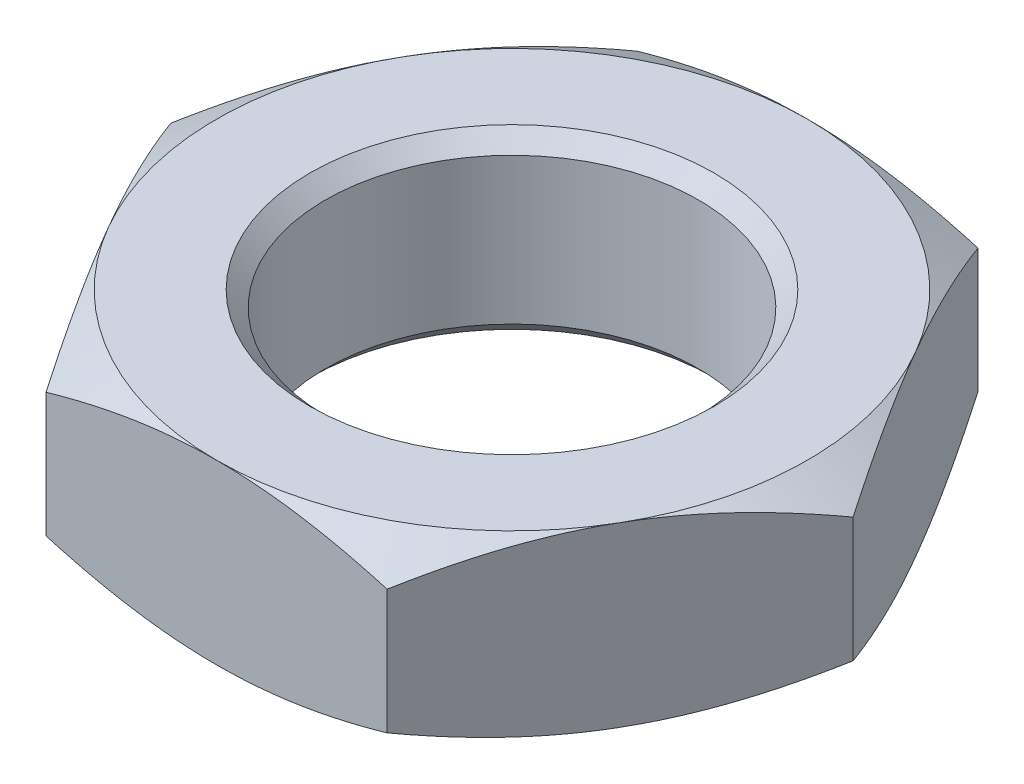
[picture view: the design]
ISO-10303-21;
HEADER;
FILE_DESCRIPTION(('STEP AP214'),'2;1');
FILE_NAME('part.step','',(''),(''),'','','');
FILE_SCHEMA(('AUTOMOTIVE_DESIGN { 1 0 10303 214 1 1 1 1 }'));
ENDSEC;
DATA;
#1=APPLICATION_CONTEXT('core data for automotive mechanical design processes');
#2=APPLICATION_PROTOCOL_DEFINITION('international standard','automotive_design',2000,#1);
#3=PRODUCT_CONTEXT('',#1,'mechanical');
#4=PRODUCT('Part','Part','',(#3));
#5=PRODUCT_RELATED_PRODUCT_CATEGORY('part','',(#4));
#6=PRODUCT_DEFINITION_FORMATION('','',#4);
#7=PRODUCT_DEFINITION_CONTEXT('part definition',#1,'design');
#8=PRODUCT_DEFINITION('design','',#6,#7);
#9=PRODUCT_DEFINITION_SHAPE('','',#8);
#10=(LENGTH_UNIT() NAMED_UNIT(*) SI_UNIT(.MILLI.,.METRE.));
#11=(NAMED_UNIT(*) PLANE_ANGLE_UNIT() SI_UNIT($,.RADIAN.));
#12=(NAMED_UNIT(*) SI_UNIT($,.STERADIAN.) SOLID_ANGLE_UNIT());
#13=UNCERTAINTY_MEASURE_WITH_UNIT(LENGTH_MEASURE(1.E-05),#10,'distance_accuracy_value','');
#14=(GEOMETRIC_REPRESENTATION_CONTEXT(3) GLOBAL_UNCERTAINTY_ASSIGNED_CONTEXT((#13)) GLOBAL_UNIT_ASSIGNED_CONTEXT((#10,
#11,#12)) REPRESENTATION_CONTEXT('',''));
#15=CARTESIAN_POINT('',(0.,0.,0.));
#16=DIRECTION('',(0.,0.,1.));
#17=DIRECTION('',(1.,0.,0.));
#18=AXIS2_PLACEMENT_3D('',#15,#16,#17);
#19=CARTESIAN_POINT('',(0.,2.85,0.));
#20=DIRECTION('',(0.,1.,0.));
#21=DIRECTION('',(0.,0.,1.));
#22=AXIS2_PLACEMENT_3D('',#19,#20,#21);
#23=PLANE('',#22);
#24=CARTESIAN_POINT('',(0.,2.85,0.));
#25=DIRECTION('',(0.,1.,0.));
#26=DIRECTION('',(0.,0.,1.));
#27=AXIS2_PLACEMENT_3D('',#24,#25,#26);
#28=CIRCLE('',#27,6.5);
#29=CARTESIAN_POINT('',(0.,2.85,6.5));
#30=VERTEX_POINT('',#29);
#31=EDGE_CURVE('E11',#30,#30,#28,.F.);
#32=ORIENTED_EDGE('',*,*,#31,.T.);
#33=EDGE_LOOP('',(#32));
#34=FACE_BOUND('',#33,.T.);
#35=CARTESIAN_POINT('',(0.,2.85,0.));
#36=DIRECTION('',(0.,1.,0.));
#37=DIRECTION('',(0.,0.,1.));
#38=AXIS2_PLACEMENT_3D('',#35,#36,#37);
#39=CIRCLE('',#38,9.5);
#40=CARTESIAN_POINT('',(-8.22724133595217,2.85,4.75));
#41=VERTEX_POINT('',#40);
#42=CARTESIAN_POINT('',(0.,2.85,9.5));
#43=VERTEX_POINT('',#42);
#44=EDGE_CURVE('E142',#41,#43,#39,.T.);
#45=ORIENTED_EDGE('',*,*,#44,.T.);
#46=CARTESIAN_POINT('',(8.22724133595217,2.85,4.75));
#47=VERTEX_POINT('',#46);
#48=EDGE_CURVE('E175',#43,#47,#39,.T.);
#49=ORIENTED_EDGE('',*,*,#48,.T.);
#50=CARTESIAN_POINT('',(8.22724133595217,2.85,-4.75));
#51=VERTEX_POINT('',#50);
#52=EDGE_CURVE('E179',#47,#51,#39,.T.);
#53=ORIENTED_EDGE('',*,*,#52,.T.);
#54=CARTESIAN_POINT('',(0.,2.85,-9.5));
#55=VERTEX_POINT('',#54);
#56=EDGE_CURVE('E361',#51,#55,#39,.T.);
#57=ORIENTED_EDGE('',*,*,#56,.T.);
#58=CARTESIAN_POINT('',(-8.22724133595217,2.85,-4.75));
#59=VERTEX_POINT('',#58);
#60=EDGE_CURVE('E55',#55,#59,#39,.T.);
#61=ORIENTED_EDGE('',*,*,#60,.T.);
#62=EDGE_CURVE('E63',#59,#41,#39,.T.);
#63=ORIENTED_EDGE('',*,*,#62,.T.);
#64=EDGE_LOOP('',(#45,#49,#53,#57,#61,#63));
#65=FACE_BOUND('',#64,.T.);
#66=ADVANCED_FACE('F39',(#34,#65),#23,.T.);
#67=CARTESIAN_POINT('',(0.,-2.85,0.));
#68=DIRECTION('',(0.,1.,0.));
#69=DIRECTION('',(0.,0.,1.));
#70=AXIS2_PLACEMENT_3D('',#67,#68,#69);
#71=PLANE('',#70);
#72=CARTESIAN_POINT('',(0.,-2.85,0.));
#73=DIRECTION('',(0.,1.,0.));
#74=DIRECTION('',(0.,0.,1.));
#75=AXIS2_PLACEMENT_3D('',#72,#73,#74);
#76=CIRCLE('',#75,6.50000000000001);
#77=CARTESIAN_POINT('',(0.,-2.85,6.50000000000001));
#78=VERTEX_POINT('',#77);
#79=EDGE_CURVE('E326',#78,#78,#76,.T.);
#80=ORIENTED_EDGE('',*,*,#79,.T.);
#81=EDGE_LOOP('',(#80));
#82=FACE_BOUND('',#81,.T.);
#83=CARTESIAN_POINT('',(0.,-2.85,0.));
#84=DIRECTION('',(0.,1.,0.));
#85=DIRECTION('',(0.,0.,1.));
#86=AXIS2_PLACEMENT_3D('',#83,#84,#85);
#87=CIRCLE('',#86,9.5);
#88=CARTESIAN_POINT('',(0.,-2.85,9.5));
#89=VERTEX_POINT('',#88);
#90=CARTESIAN_POINT('',(8.22724133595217,-2.85,4.75));
#91=VERTEX_POINT('',#90);
#92=EDGE_CURVE('E130',#89,#91,#87,.T.);
#93=ORIENTED_EDGE('',*,*,#92,.F.);
#94=CARTESIAN_POINT('',(-8.22724133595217,-2.85,4.75));
#95=VERTEX_POINT('',#94);
#96=EDGE_CURVE('E145',#95,#89,#87,.T.);
#97=ORIENTED_EDGE('',*,*,#96,.F.);
#98=CARTESIAN_POINT('',(-8.22724133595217,-2.85,-4.75));
#99=VERTEX_POINT('',#98);
#100=EDGE_CURVE('E367',#99,#95,#87,.T.);
#101=ORIENTED_EDGE('',*,*,#100,.F.);
#102=CARTESIAN_POINT('',(0.,-2.85,-9.5));
#103=VERTEX_POINT('',#102);
#104=EDGE_CURVE('E173',#103,#99,#87,.T.);
#105=ORIENTED_EDGE('',*,*,#104,.F.);
#106=CARTESIAN_POINT('',(8.22724133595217,-2.85,-4.75));
#107=VERTEX_POINT('',#106);
#108=EDGE_CURVE('E169',#107,#103,#87,.T.);
#109=ORIENTED_EDGE('',*,*,#108,.F.);
#110=EDGE_CURVE('E143',#91,#107,#87,.T.);
#111=ORIENTED_EDGE('',*,*,#110,.F.);
#112=EDGE_LOOP('',(#93,#97,#101,#105,#109,#111));
#113=FACE_BOUND('',#112,.T.);
#114=ADVANCED_FACE('F167',(#82,#113),#71,.F.);
#115=CARTESIAN_POINT('',(0.,2.85,0.));
#116=DIRECTION('',(0.,-1.,0.));
#117=DIRECTION('',(0.,0.,-1.));
#118=AXIS2_PLACEMENT_3D('',#115,#116,#117);
#119=CYLINDRICAL_SURFACE('',#118,6.);
#120=CARTESIAN_POINT('',(0.,-2.34999999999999,0.));
#121=DIRECTION('',(0.,1.,0.));
#122=DIRECTION('',(0.,0.,1.));
#123=AXIS2_PLACEMENT_3D('',#120,#121,#122);
#124=CIRCLE('',#123,6.);
#125=CARTESIAN_POINT('',(0.,-2.34999999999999,6.));
#126=VERTEX_POINT('',#125);
#127=EDGE_CURVE('E48',#126,#126,#124,.F.);
#128=ORIENTED_EDGE('',*,*,#127,.T.);
#129=EDGE_LOOP('',(#128));
#130=FACE_BOUND('',#129,.T.);
#131=CARTESIAN_POINT('',(0.,2.35,0.));
#132=DIRECTION('',(0.,1.,0.));
#133=DIRECTION('',(0.,0.,1.));
#134=AXIS2_PLACEMENT_3D('',#131,#132,#133);
#135=CIRCLE('',#134,6.);
#136=CARTESIAN_POINT('',(0.,2.35,6.));
#137=VERTEX_POINT('',#136);
#138=EDGE_CURVE('E330',#137,#137,#135,.T.);
#139=ORIENTED_EDGE('',*,*,#138,.T.);
#140=EDGE_LOOP('',(#139));
#141=FACE_BOUND('',#140,.T.);
#142=ADVANCED_FACE('F202',(#130,#141),#119,.F.);
#143=CARTESIAN_POINT('',(0.,-2.85,0.));
#144=DIRECTION('',(0.,1.,0.));
#145=DIRECTION('',(0.,0.,1.));
#146=AXIS2_PLACEMENT_3D('',#143,#144,#145);
#147=CONICAL_SURFACE('',#146,9.5,1.0471975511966);
#148=CARTESIAN_POINT('',(5.4847120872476,-2.00142755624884,9.5002));
#149=CARTESIAN_POINT('',(5.60528058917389,-2.07102656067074,9.2913692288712));
#150=CARTESIAN_POINT('',(5.72629863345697,-2.13746669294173,9.08175982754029));
#151=CARTESIAN_POINT('',(5.96930519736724,-2.26315271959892,8.66086011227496));
#152=CARTESIAN_POINT('',(6.09129402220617,-2.32239624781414,8.44956926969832));
#153=CARTESIAN_POINT('',(6.45922610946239,-2.48818542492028,7.81229220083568));
#154=CARTESIAN_POINT('',(6.70662183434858,-2.58248555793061,7.38379023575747));
#155=CARTESIAN_POINT('',(7.07683821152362,-2.69306129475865,6.74255666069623));
#156=CARTESIAN_POINT('',(7.19855281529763,-2.72456017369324,6.53174078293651));
#157=CARTESIAN_POINT('',(7.44254555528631,-2.77738179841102,6.10913296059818));
#158=CARTESIAN_POINT('',(7.56482370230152,-2.79870434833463,5.89734099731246));
#159=CARTESIAN_POINT('',(7.80958396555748,-2.83062697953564,5.47340378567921));
#160=CARTESIAN_POINT('',(7.93206566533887,-2.84123980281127,5.26125925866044));
#161=CARTESIAN_POINT('',(8.17714220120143,-2.85151746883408,4.83677424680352));
#162=CARTESIAN_POINT('',(8.29973703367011,-2.85118264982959,4.62443376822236));
#163=CARTESIAN_POINT('',(8.5289310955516,-2.84032663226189,4.22745800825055));
#164=CARTESIAN_POINT('',(8.63554650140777,-2.83112973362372,4.04279470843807));
#165=CARTESIAN_POINT('',(8.84852796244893,-2.80463460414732,3.67389999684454));
#166=CARTESIAN_POINT('',(8.95489399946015,-2.78733580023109,3.48966861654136));
#167=CARTESIAN_POINT('',(9.27357996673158,-2.72369551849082,2.937688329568));
#168=CARTESIAN_POINT('',(9.48533580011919,-2.66561809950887,2.57091646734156));
#169=CARTESIAN_POINT('',(9.91109368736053,-2.52042398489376,1.83348217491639));
#170=CARTESIAN_POINT('',(10.1250414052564,-2.43269183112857,1.46291385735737));
#171=CARTESIAN_POINT('',(10.5497463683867,-2.23357626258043,0.72730328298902));
#172=CARTESIAN_POINT('',(10.7605090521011,-2.12223961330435,0.362251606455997));
#173=CARTESIAN_POINT('',(10.9697705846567,-2.00142755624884,-0.000200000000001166));
#174=B_SPLINE_CURVE_WITH_KNOTS('',3,(#148,#149,#150,#151,#152,#153,#154,#155,#156,#157,#158,
#159,#160,#161,#162,#163,#164,#165,#166,#167,#168,#169,#170,#171,#172,#173),.UNSPECIFIED.,.F.,
.F.,(4,2,2,2,2,2,2,2,2,2,2,2,4),(0.,0.752880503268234,1.50600787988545,3.0154687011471,
3.75167336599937,4.48789219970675,5.22323407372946,5.95855322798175,6.59868084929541,
7.23885375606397,8.52010929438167,9.82978009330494,11.1368800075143),.UNSPECIFIED.);
#175=CARTESIAN_POINT('',(10.9696551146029,-2.00149422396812,0.));
#176=VERTEX_POINT('',#175);
#177=EDGE_CURVE('E148',#91,#176,#174,.T.);
#178=ORIENTED_EDGE('',*,*,#177,.F.);
#179=ORIENTED_EDGE('',*,*,#110,.T.);
#180=CARTESIAN_POINT('',(10.9697705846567,-2.00142755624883,0.000199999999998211));
#181=CARTESIAN_POINT('',(10.8492020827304,-2.07102656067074,-0.208630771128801));
#182=CARTESIAN_POINT('',(10.7281840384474,-2.13746669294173,-0.41824017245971));
#183=CARTESIAN_POINT('',(10.4851774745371,-2.26315271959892,-0.839139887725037));
#184=CARTESIAN_POINT('',(10.3631886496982,-2.32239624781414,-1.05043073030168));
#185=CARTESIAN_POINT('',(9.99525656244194,-2.48818542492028,-1.68770779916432));
#186=CARTESIAN_POINT('',(9.74786083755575,-2.58248555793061,-2.11620976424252));
#187=CARTESIAN_POINT('',(9.37764446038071,-2.69306129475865,-2.75744333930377));
#188=CARTESIAN_POINT('',(9.2559298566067,-2.72456017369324,-2.96825921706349));
#189=CARTESIAN_POINT('',(9.01193711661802,-2.77738179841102,-3.39086703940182));
#190=CARTESIAN_POINT('',(8.88965896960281,-2.79870434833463,-3.60265900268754));
#191=CARTESIAN_POINT('',(8.64489870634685,-2.83062697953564,-4.02659621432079));
#192=CARTESIAN_POINT('',(8.52241700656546,-2.84123980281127,-4.23874074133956));
#193=CARTESIAN_POINT('',(8.2773404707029,-2.85151746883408,-4.66322575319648));
#194=CARTESIAN_POINT('',(8.15474563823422,-2.85118264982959,-4.87556623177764));
#195=CARTESIAN_POINT('',(7.92555157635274,-2.84032663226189,-5.27254199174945));
#196=CARTESIAN_POINT('',(7.81893617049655,-2.83112973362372,-5.45720529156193));
#197=CARTESIAN_POINT('',(7.6059547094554,-2.80463460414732,-5.82610000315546));
#198=CARTESIAN_POINT('',(7.49958867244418,-2.78733580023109,-6.01033138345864));
#199=CARTESIAN_POINT('',(7.18090270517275,-2.72369551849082,-6.562311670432));
#200=CARTESIAN_POINT('',(6.96914687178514,-2.66561809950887,-6.92908353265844));
#201=CARTESIAN_POINT('',(6.5433889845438,-2.52042398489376,-7.66651782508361));
#202=CARTESIAN_POINT('',(6.32944126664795,-2.43269183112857,-8.03708614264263));
#203=CARTESIAN_POINT('',(5.90473630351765,-2.23357626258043,-8.77269671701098));
#204=CARTESIAN_POINT('',(5.69397361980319,-2.12223961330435,-9.137748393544));
#205=CARTESIAN_POINT('',(5.4847120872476,-2.00142755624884,-9.5002));
#206=B_SPLINE_CURVE_WITH_KNOTS('',3,(#180,#181,#182,#183,#184,#185,#186,#187,#188,#189,#190,
#191,#192,#193,#194,#195,#196,#197,#198,#199,#200,#201,#202,#203,#204,#205),.UNSPECIFIED.,.F.,
.F.,(4,2,2,2,2,2,2,2,2,2,2,2,4),(0.,0.752880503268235,1.50600787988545,3.0154687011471,
3.75167336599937,4.48789219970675,5.22323407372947,5.95855322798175,6.5986808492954,
7.23885375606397,8.52010929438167,9.82978009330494,11.1368800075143),.UNSPECIFIED.);
#207=EDGE_CURVE('E152',#176,#107,#206,.T.);
#208=ORIENTED_EDGE('',*,*,#207,.F.);
#209=EDGE_LOOP('',(#178,#179,#208));
#210=FACE_BOUND('',#209,.T.);
#211=ADVANCED_FACE('F149',(#210),#147,.T.);
#212=ORIENTED_EDGE('',*,*,#92,.T.);
#213=CARTESIAN_POINT('',(5.48482755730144,-2.00149422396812,9.5));
#214=VERTEX_POINT('',#213);
#215=EDGE_CURVE('E134',#214,#91,#174,.T.);
#216=ORIENTED_EDGE('',*,*,#215,.F.);
#217=CARTESIAN_POINT('',(-16.8188633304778,2.81751395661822,9.50000000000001));
#218=CARTESIAN_POINT('',(-16.4183500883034,2.61620642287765,9.50000000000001));
#219=CARTESIAN_POINT('',(-16.0171570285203,2.41623761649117,9.50000000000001));
#220=CARTESIAN_POINT('',(-15.2130991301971,2.01962708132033,9.50000000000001));
#221=CARTESIAN_POINT('',(-14.8102341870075,1.82298556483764,9.50000000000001));
#222=CARTESIAN_POINT('',(-14.0017844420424,1.43332577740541,9.50000000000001));
#223=CARTESIAN_POINT('',(-13.5961958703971,1.24031531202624,9.5));
#224=CARTESIAN_POINT('',(-12.7827179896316,0.859216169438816,9.5));
#225=CARTESIAN_POINT('',(-12.3748287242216,0.671127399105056,9.5));
#226=CARTESIAN_POINT('',(-11.537358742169,0.292449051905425,9.5));
#227=CARTESIAN_POINT('',(-11.1076477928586,0.102146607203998,9.5));
#228=CARTESIAN_POINT('',(-10.2445855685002,-0.270106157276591,9.5));
#229=CARTESIAN_POINT('',(-9.81123413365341,-0.452056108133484,9.5));
#230=CARTESIAN_POINT('',(-8.94045769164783,-0.805201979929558,9.5));
#231=CARTESIAN_POINT('',(-8.50303531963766,-0.976404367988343,9.5));
#232=CARTESIAN_POINT('',(-7.62309223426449,-1.30515393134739,9.5));
#233=CARTESIAN_POINT('',(-7.18057207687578,-1.46270258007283,9.5));
#234=CARTESIAN_POINT('',(-6.46275750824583,-1.7023816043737,9.5));
#235=CARTESIAN_POINT('',(-6.1893097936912,-1.79002659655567,9.5));
#236=CARTESIAN_POINT('',(-5.64007283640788,-1.95762798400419,9.5));
#237=CARTESIAN_POINT('',(-5.36428350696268,-2.03758409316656,9.5));
#238=CARTESIAN_POINT('',(-4.53319488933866,-2.26409391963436,9.5));
#239=CARTESIAN_POINT('',(-3.97407836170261,-2.39732227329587,9.5));
#240=CARTESIAN_POINT('',(-3.13352758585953,-2.56129439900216,9.5));
#241=CARTESIAN_POINT('',(-2.85548786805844,-2.60969970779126,9.5));
#242=CARTESIAN_POINT('',(-2.29749624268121,-2.69402319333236,9.5));
#243=CARTESIAN_POINT('',(-2.01754436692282,-2.72994157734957,9.5));
#244=CARTESIAN_POINT('',(-1.45632964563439,-2.78821437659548,9.5));
#245=CARTESIAN_POINT('',(-1.17506733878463,-2.81057394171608,9.5));
#246=CARTESIAN_POINT('',(-0.611764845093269,-2.84102373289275,9.5));
#247=CARTESIAN_POINT('',(-0.32972466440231,-2.84911407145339,9.5));
#248=CARTESIAN_POINT('',(0.236413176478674,-2.8507537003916,9.5));
#249=CARTESIAN_POINT('',(0.520511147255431,-2.84419874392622,9.5));
#250=CARTESIAN_POINT('',(1.08799392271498,-2.8165616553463,9.5));
#251=CARTESIAN_POINT('',(1.37137871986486,-2.79547937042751,9.5));
#252=CARTESIAN_POINT('',(1.93687689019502,-2.73947689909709,9.5));
#253=CARTESIAN_POINT('',(2.21898973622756,-2.7045514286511,9.5));
#254=CARTESIAN_POINT('',(2.78131252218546,-2.62192625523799,9.5));
#255=CARTESIAN_POINT('',(3.06152243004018,-2.57422633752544,9.5));
#256=CARTESIAN_POINT('',(3.90869402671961,-2.4119698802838,9.5));
#257=CARTESIAN_POINT('',(4.47224297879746,-2.27931766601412,9.5));
#258=CARTESIAN_POINT('',(5.30985754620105,-2.05301216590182,9.5));
#259=CARTESIAN_POINT('',(5.58780518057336,-1.97301304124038,9.5));
#260=CARTESIAN_POINT('',(6.14131764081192,-1.80514200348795,9.5));
#261=CARTESIAN_POINT('',(6.41688255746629,-1.71727039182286,9.5));
#262=CARTESIAN_POINT('',(7.13891911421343,-1.47722823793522,9.5));
#263=CARTESIAN_POINT('',(7.583527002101,-1.31946861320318,9.5));
#264=CARTESIAN_POINT('',(8.46757838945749,-0.990079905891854,9.5));
#265=CARTESIAN_POINT('',(8.90702131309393,-0.818449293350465,9.5));
#266=CARTESIAN_POINT('',(9.78178536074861,-0.464290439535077,9.5));
#267=CARTESIAN_POINT('',(10.2171037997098,-0.281755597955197,9.5));
#268=CARTESIAN_POINT('',(11.0840547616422,0.0917784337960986,9.5));
#269=CARTESIAN_POINT('',(11.5156874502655,0.282777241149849,9.5));
#270=CARTESIAN_POINT('',(12.3567622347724,0.662842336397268,9.5));
#271=CARTESIAN_POINT('',(12.7663368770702,0.851616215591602,9.5));
#272=CARTESIAN_POINT('',(13.5831621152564,1.23413764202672,9.5));
#273=CARTESIAN_POINT('',(13.9904126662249,1.42788528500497,9.49999999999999));
#274=CARTESIAN_POINT('',(14.8021509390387,1.81904999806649,9.49999999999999));
#275=CARTESIAN_POINT('',(15.2066425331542,2.01645904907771,9.49999999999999));
#276=CARTESIAN_POINT('',(16.0139388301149,2.41463385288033,9.49999999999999));
#277=CARTESIAN_POINT('',(16.4167436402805,2.61539938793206,9.49999999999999));
#278=CARTESIAN_POINT('',(16.8188633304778,2.81751395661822,9.49999999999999));
#279=B_SPLINE_CURVE_WITH_KNOTS('',3,(#217,#218,#219,#220,#221,#222,#223,#224,#225,#226,#227,
#228,#229,#230,#231,#232,#233,#234,#235,#236,#237,#238,#239,#240,#241,#242,#243,#244,#245,#246,
#247,#248,#249,#250,#251,#252,#253,#254,#255,#256,#257,#258,#259,#260,#261,#262,#263,#264,#265,
#266,#267,#268,#269,#270,#271,#272,#273,#274,#275,#276,#277,#278),.UNSPECIFIED.,.F.,.F.,(4,2,2,
2,2,2,2,2,2,2,2,2,2,2,2,2,2,2,2,2,2,2,2,2,2,2,2,2,2,2,4),(0.,1.34478189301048,2.68964927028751,
4.03713684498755,5.38459890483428,6.79442275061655,8.20430880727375,9.61333819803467,
11.0222153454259,11.883557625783,12.7449319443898,14.4673746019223,15.3138133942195,
16.1602381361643,17.0063411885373,17.8524375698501,18.7045757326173,19.5567228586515,
20.4091955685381,21.2616826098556,22.9965895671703,23.8642177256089,24.7318126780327,
26.1467947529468,27.5619331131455,28.977936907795,30.3938767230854,31.7467902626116,
33.0997298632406,34.4499924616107,35.8001678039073),.UNSPECIFIED.);
#280=EDGE_CURVE('E136',#89,#214,#279,.T.);
#281=ORIENTED_EDGE('',*,*,#280,.F.);
#282=EDGE_LOOP('',(#212,#216,#281));
#283=FACE_BOUND('',#282,.T.);
#284=ADVANCED_FACE('F132',(#283),#147,.T.);
#285=CARTESIAN_POINT('',(0.,2.85,0.));
#286=DIRECTION('',(0.,-1.,0.));
#287=DIRECTION('',(0.,0.,-1.));
#288=AXIS2_PLACEMENT_3D('',#285,#286,#287);
#289=CONICAL_SURFACE('',#288,9.5,1.0471975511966);
#290=CARTESIAN_POINT('',(10.9697705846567,2.00142755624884,0.000199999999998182));
#291=CARTESIAN_POINT('',(10.8492020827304,2.07102656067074,-0.208630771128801));
#292=CARTESIAN_POINT('',(10.7281840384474,2.13746669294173,-0.41824017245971));
#293=CARTESIAN_POINT('',(10.4851774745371,2.26315271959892,-0.839139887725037));
#294=CARTESIAN_POINT('',(10.3631886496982,2.32239624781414,-1.05043073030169));
#295=CARTESIAN_POINT('',(9.99525656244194,2.48818542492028,-1.68770779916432));
#296=CARTESIAN_POINT('',(9.74786083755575,2.58248555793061,-2.11620976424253));
#297=CARTESIAN_POINT('',(9.37764446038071,2.69306129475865,-2.75744333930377));
#298=CARTESIAN_POINT('',(9.25592985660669,2.72456017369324,-2.96825921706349));
#299=CARTESIAN_POINT('',(9.01193711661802,2.77738179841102,-3.39086703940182));
#300=CARTESIAN_POINT('',(8.88965896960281,2.79870434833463,-3.60265900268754));
#301=CARTESIAN_POINT('',(8.64489870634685,2.83062697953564,-4.02659621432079));
#302=CARTESIAN_POINT('',(8.52241700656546,2.84123980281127,-4.23874074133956));
#303=CARTESIAN_POINT('',(8.2773404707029,2.85151746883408,-4.66322575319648));
#304=CARTESIAN_POINT('',(8.15474563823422,2.85118264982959,-4.87556623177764));
#305=CARTESIAN_POINT('',(7.92555157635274,2.84032663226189,-5.27254199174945));
#306=CARTESIAN_POINT('',(7.81893617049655,2.83112973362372,-5.45720529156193));
#307=CARTESIAN_POINT('',(7.6059547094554,2.80463460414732,-5.82610000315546));
#308=CARTESIAN_POINT('',(7.49958867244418,2.78733580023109,-6.01033138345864));
#309=CARTESIAN_POINT('',(7.18090270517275,2.72369551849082,-6.562311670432));
#310=CARTESIAN_POINT('',(6.96914687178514,2.66561809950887,-6.92908353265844));
#311=CARTESIAN_POINT('',(6.5433889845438,2.52042398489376,-7.66651782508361));
#312=CARTESIAN_POINT('',(6.32944126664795,2.43269183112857,-8.03708614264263));
#313=CARTESIAN_POINT('',(5.90473630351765,2.23357626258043,-8.77269671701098));
#314=CARTESIAN_POINT('',(5.69397361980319,2.12223961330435,-9.137748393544));
#315=CARTESIAN_POINT('',(5.4847120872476,2.00142755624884,-9.5002));
#316=B_SPLINE_CURVE_WITH_KNOTS('',3,(#290,#291,#292,#293,#294,#295,#296,#297,#298,#299,#300,
#301,#302,#303,#304,#305,#306,#307,#308,#309,#310,#311,#312,#313,#314,#315),.UNSPECIFIED.,.F.,
.F.,(4,2,2,2,2,2,2,2,2,2,2,2,4),(0.,0.752880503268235,1.50600787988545,3.0154687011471,
3.75167336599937,4.48789219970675,5.22323407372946,5.95855322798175,6.5986808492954,
7.23885375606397,8.52010929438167,9.82978009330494,11.1368800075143),.UNSPECIFIED.);
#317=CARTESIAN_POINT('',(10.9696551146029,2.00149422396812,0.));
#318=VERTEX_POINT('',#317);
#319=EDGE_CURVE('E276',#318,#51,#316,.T.);
#320=ORIENTED_EDGE('',*,*,#319,.T.);
#321=ORIENTED_EDGE('',*,*,#52,.F.);
#322=CARTESIAN_POINT('',(5.4847120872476,2.00142755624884,9.5002));
#323=CARTESIAN_POINT('',(5.60528058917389,2.07102656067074,9.2913692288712));
#324=CARTESIAN_POINT('',(5.72629863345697,2.13746669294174,9.08175982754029));
#325=CARTESIAN_POINT('',(5.96930519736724,2.26315271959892,8.66086011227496));
#326=CARTESIAN_POINT('',(6.09129402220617,2.32239624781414,8.44956926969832));
#327=CARTESIAN_POINT('',(6.45922610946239,2.48818542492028,7.81229220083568));
#328=CARTESIAN_POINT('',(6.70662183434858,2.58248555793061,7.38379023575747));
#329=CARTESIAN_POINT('',(7.07683821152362,2.69306129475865,6.74255666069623));
#330=CARTESIAN_POINT('',(7.19855281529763,2.72456017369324,6.53174078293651));
#331=CARTESIAN_POINT('',(7.44254555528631,2.77738179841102,6.10913296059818));
#332=CARTESIAN_POINT('',(7.56482370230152,2.79870434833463,5.89734099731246));
#333=CARTESIAN_POINT('',(7.80958396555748,2.83062697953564,5.47340378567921));
#334=CARTESIAN_POINT('',(7.93206566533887,2.84123980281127,5.26125925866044));
#335=CARTESIAN_POINT('',(8.17714220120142,2.85151746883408,4.83677424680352));
#336=CARTESIAN_POINT('',(8.29973703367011,2.85118264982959,4.62443376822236));
#337=CARTESIAN_POINT('',(8.52893109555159,2.84032663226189,4.22745800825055));
#338=CARTESIAN_POINT('',(8.63554650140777,2.83112973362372,4.04279470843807));
#339=CARTESIAN_POINT('',(8.84852796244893,2.80463460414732,3.67389999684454));
#340=CARTESIAN_POINT('',(8.95489399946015,2.78733580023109,3.48966861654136));
#341=CARTESIAN_POINT('',(9.27357996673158,2.72369551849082,2.937688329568));
#342=CARTESIAN_POINT('',(9.48533580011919,2.66561809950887,2.57091646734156));
#343=CARTESIAN_POINT('',(9.91109368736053,2.52042398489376,1.83348217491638));
#344=CARTESIAN_POINT('',(10.1250414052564,2.43269183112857,1.46291385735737));
#345=CARTESIAN_POINT('',(10.5497463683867,2.23357626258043,0.727303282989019));
#346=CARTESIAN_POINT('',(10.7605090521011,2.12223961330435,0.362251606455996));
#347=CARTESIAN_POINT('',(10.9697705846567,2.00142755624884,-0.000200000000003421));
#348=B_SPLINE_CURVE_WITH_KNOTS('',3,(#322,#323,#324,#325,#326,#327,#328,#329,#330,#331,#332,
#333,#334,#335,#336,#337,#338,#339,#340,#341,#342,#343,#344,#345,#346,#347),.UNSPECIFIED.,.F.,
.F.,(4,2,2,2,2,2,2,2,2,2,2,2,4),(0.,0.752880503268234,1.50600787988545,3.0154687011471,
3.75167336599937,4.48789219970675,5.22323407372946,5.95855322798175,6.59868084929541,
7.23885375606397,8.52010929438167,9.82978009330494,11.1368800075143),.UNSPECIFIED.);
#349=EDGE_CURVE('E165',#47,#318,#348,.T.);
#350=ORIENTED_EDGE('',*,*,#349,.T.);
#351=EDGE_LOOP('',(#320,#321,#350));
#352=FACE_BOUND('',#351,.T.);
#353=ADVANCED_FACE('F204',(#352),#289,.T.);
#354=CARTESIAN_POINT('',(-16.8188633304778,-2.81751395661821,9.50000000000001));
#355=CARTESIAN_POINT('',(-16.4183500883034,-2.61620642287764,9.50000000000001));
#356=CARTESIAN_POINT('',(-16.0171570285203,-2.41623761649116,9.50000000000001));
#357=CARTESIAN_POINT('',(-15.2130991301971,-2.01962708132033,9.50000000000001));
#358=CARTESIAN_POINT('',(-14.8102341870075,-1.82298556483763,9.50000000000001));
#359=CARTESIAN_POINT('',(-14.0017844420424,-1.4333257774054,9.50000000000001));
#360=CARTESIAN_POINT('',(-13.5961958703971,-1.24031531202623,9.5));
#361=CARTESIAN_POINT('',(-12.7827179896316,-0.859216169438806,9.5));
#362=CARTESIAN_POINT('',(-12.3748287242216,-0.671127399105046,9.5));
#363=CARTESIAN_POINT('',(-11.537358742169,-0.292449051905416,9.5));
#364=CARTESIAN_POINT('',(-11.1076477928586,-0.102146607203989,9.5));
#365=CARTESIAN_POINT('',(-10.2445855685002,0.270106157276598,9.5));
#366=CARTESIAN_POINT('',(-9.81123413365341,0.452056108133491,9.5));
#367=CARTESIAN_POINT('',(-8.94045769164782,0.805201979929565,9.5));
#368=CARTESIAN_POINT('',(-8.50303531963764,0.976404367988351,9.5));
#369=CARTESIAN_POINT('',(-7.62309223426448,1.3051539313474,9.5));
#370=CARTESIAN_POINT('',(-7.18057207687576,1.46270258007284,9.5));
#371=CARTESIAN_POINT('',(-6.46275750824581,1.70238160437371,9.5));
#372=CARTESIAN_POINT('',(-6.18930979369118,1.79002659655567,9.5));
#373=CARTESIAN_POINT('',(-5.64007283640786,1.9576279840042,9.5));
#374=CARTESIAN_POINT('',(-5.36428350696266,2.03758409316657,9.5));
#375=CARTESIAN_POINT('',(-4.53319488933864,2.26409391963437,9.5));
#376=CARTESIAN_POINT('',(-3.97407836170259,2.39732227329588,9.5));
#377=CARTESIAN_POINT('',(-3.1335275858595,2.56129439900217,9.5));
#378=CARTESIAN_POINT('',(-2.85548786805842,2.60969970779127,9.5));
#379=CARTESIAN_POINT('',(-2.29749624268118,2.69402319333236,9.5));
#380=CARTESIAN_POINT('',(-2.01754436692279,2.72994157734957,9.5));
#381=CARTESIAN_POINT('',(-1.45632964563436,2.78821437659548,9.5));
#382=CARTESIAN_POINT('',(-1.1750673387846,2.81057394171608,9.5));
#383=CARTESIAN_POINT('',(-0.611764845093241,2.84102373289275,9.5));
#384=CARTESIAN_POINT('',(-0.329724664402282,2.84911407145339,9.5));
#385=CARTESIAN_POINT('',(0.236413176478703,2.8507537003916,9.5));
#386=CARTESIAN_POINT('',(0.52051114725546,2.84419874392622,9.5));
#387=CARTESIAN_POINT('',(1.08799392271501,2.8165616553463,9.5));
#388=CARTESIAN_POINT('',(1.37137871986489,2.7954793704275,9.5));
#389=CARTESIAN_POINT('',(1.93687689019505,2.73947689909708,9.5));
#390=CARTESIAN_POINT('',(2.21898973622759,2.70455142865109,9.5));
#391=CARTESIAN_POINT('',(2.78131252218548,2.62192625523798,9.5));
#392=CARTESIAN_POINT('',(3.06152243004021,2.57422633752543,9.5));
#393=CARTESIAN_POINT('',(3.90869402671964,2.4119698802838,9.5));
#394=CARTESIAN_POINT('',(4.47224297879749,2.27931766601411,9.5));
#395=CARTESIAN_POINT('',(5.30985754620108,2.05301216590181,9.5));
#396=CARTESIAN_POINT('',(5.58780518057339,1.97301304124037,9.5));
#397=CARTESIAN_POINT('',(6.14131764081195,1.80514200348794,9.5));
#398=CARTESIAN_POINT('',(6.41688255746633,1.71727039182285,9.5));
#399=CARTESIAN_POINT('',(7.13891911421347,1.47722823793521,9.5));
#400=CARTESIAN_POINT('',(7.58352700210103,1.31946861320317,9.5));
#401=CARTESIAN_POINT('',(8.46757838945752,0.990079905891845,9.5));
#402=CARTESIAN_POINT('',(8.90702131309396,0.818449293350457,9.5));
#403=CARTESIAN_POINT('',(9.78178536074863,0.46429043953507,9.5));
#404=CARTESIAN_POINT('',(10.2171037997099,0.281755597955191,9.5));
#405=CARTESIAN_POINT('',(11.0840547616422,-0.0917784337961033,9.5));
#406=CARTESIAN_POINT('',(11.5156874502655,-0.282777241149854,9.5));
#407=CARTESIAN_POINT('',(12.3567622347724,-0.662842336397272,9.5));
#408=CARTESIAN_POINT('',(12.7663368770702,-0.851616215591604,9.5));
#409=CARTESIAN_POINT('',(13.5831621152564,-1.23413764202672,9.5));
#410=CARTESIAN_POINT('',(13.9904126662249,-1.42788528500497,9.49999999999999));
#411=CARTESIAN_POINT('',(14.8021509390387,-1.81904999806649,9.49999999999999));
#412=CARTESIAN_POINT('',(15.2066425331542,-2.0164590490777,9.49999999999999));
#413=CARTESIAN_POINT('',(16.0139388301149,-2.41463385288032,9.49999999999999));
#414=CARTESIAN_POINT('',(16.4167436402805,-2.61539938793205,9.49999999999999));
#415=CARTESIAN_POINT('',(16.8188633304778,-2.81751395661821,9.49999999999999));
#416=B_SPLINE_CURVE_WITH_KNOTS('',3,(#354,#355,#356,#357,#358,#359,#360,#361,#362,#363,#364,
#365,#366,#367,#368,#369,#370,#371,#372,#373,#374,#375,#376,#377,#378,#379,#380,#381,#382,#383,
#384,#385,#386,#387,#388,#389,#390,#391,#392,#393,#394,#395,#396,#397,#398,#399,#400,#401,#402,
#403,#404,#405,#406,#407,#408,#409,#410,#411,#412,#413,#414,#415),.UNSPECIFIED.,.F.,.F.,(4,2,2,
2,2,2,2,2,2,2,2,2,2,2,2,2,2,2,2,2,2,2,2,2,2,2,2,2,2,2,4),(0.,1.34478189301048,2.68964927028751,
4.03713684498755,5.38459890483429,6.79442275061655,8.20430880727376,9.61333819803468,
11.0222153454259,11.883557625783,12.7449319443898,14.4673746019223,15.3138133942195,
16.1602381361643,17.0063411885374,17.8524375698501,18.7045757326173,19.5567228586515,
20.4091955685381,21.2616826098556,22.9965895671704,23.864217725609,24.7318126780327,
26.1467947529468,27.5619331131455,28.977936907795,30.3938767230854,31.7467902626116,
33.0997298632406,34.4499924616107,35.8001678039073),.UNSPECIFIED.);
#417=CARTESIAN_POINT('',(5.48482755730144,2.00149422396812,9.5));
#418=VERTEX_POINT('',#417);
#419=EDGE_CURVE('E310',#43,#418,#416,.T.);
#420=ORIENTED_EDGE('',*,*,#419,.T.);
#421=EDGE_CURVE('E317',#418,#47,#348,.T.);
#422=ORIENTED_EDGE('',*,*,#421,.T.);
#423=ORIENTED_EDGE('',*,*,#48,.F.);
#424=EDGE_LOOP('',(#420,#422,#423));
#425=FACE_BOUND('',#424,.T.);
#426=ADVANCED_FACE('F324',(#425),#289,.T.);
#427=ORIENTED_EDGE('',*,*,#96,.T.);
#428=CARTESIAN_POINT('',(-5.48482755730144,-2.00149422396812,9.5));
#429=VERTEX_POINT('',#428);
#430=EDGE_CURVE('E188',#429,#89,#279,.T.);
#431=ORIENTED_EDGE('',*,*,#430,.F.);
#432=CARTESIAN_POINT('',(-10.9697705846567,-2.00142755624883,-0.000199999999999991));
#433=CARTESIAN_POINT('',(-10.8492020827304,-2.07102656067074,0.2086307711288));
#434=CARTESIAN_POINT('',(-10.7281840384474,-2.13746669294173,0.418240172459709));
#435=CARTESIAN_POINT('',(-10.4851774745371,-2.26315271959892,0.839139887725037));
#436=CARTESIAN_POINT('',(-10.3631886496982,-2.32239624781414,1.05043073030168));
#437=CARTESIAN_POINT('',(-9.99525656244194,-2.48818542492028,1.68770779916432));
#438=CARTESIAN_POINT('',(-9.74786083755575,-2.58248555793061,2.11620976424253));
#439=CARTESIAN_POINT('',(-9.37764446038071,-2.69306129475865,2.75744333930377));
#440=CARTESIAN_POINT('',(-9.25592985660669,-2.72456017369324,2.96825921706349));
#441=CARTESIAN_POINT('',(-9.01193711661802,-2.77738179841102,3.39086703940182));
#442=CARTESIAN_POINT('',(-8.88965896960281,-2.79870434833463,3.60265900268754));
#443=CARTESIAN_POINT('',(-8.64489870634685,-2.83062697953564,4.02659621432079));
#444=CARTESIAN_POINT('',(-8.52241700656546,-2.84123980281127,4.23874074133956));
#445=CARTESIAN_POINT('',(-8.2773404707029,-2.85151746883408,4.66322575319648));
#446=CARTESIAN_POINT('',(-8.15474563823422,-2.85118264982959,4.87556623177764));
#447=CARTESIAN_POINT('',(-7.92555157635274,-2.84032663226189,5.27254199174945));
#448=CARTESIAN_POINT('',(-7.81893617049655,-2.83112973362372,5.45720529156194));
#449=CARTESIAN_POINT('',(-7.6059547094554,-2.80463460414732,5.82610000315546));
#450=CARTESIAN_POINT('',(-7.49958867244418,-2.78733580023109,6.01033138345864));
#451=CARTESIAN_POINT('',(-7.18090270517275,-2.72369551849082,6.562311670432));
#452=CARTESIAN_POINT('',(-6.96914687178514,-2.66561809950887,6.92908353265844));
#453=CARTESIAN_POINT('',(-6.5433889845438,-2.52042398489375,7.66651782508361));
#454=CARTESIAN_POINT('',(-6.32944126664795,-2.43269183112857,8.03708614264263));
#455=CARTESIAN_POINT('',(-5.90473630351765,-2.23357626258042,8.77269671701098));
#456=CARTESIAN_POINT('',(-5.69397361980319,-2.12223961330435,9.137748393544));
#457=CARTESIAN_POINT('',(-5.48471208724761,-2.00142755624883,9.5002));
#458=B_SPLINE_CURVE_WITH_KNOTS('',3,(#432,#433,#434,#435,#436,#437,#438,#439,#440,#441,#442,
#443,#444,#445,#446,#447,#448,#449,#450,#451,#452,#453,#454,#455,#456,#457),.UNSPECIFIED.,.F.,
.F.,(4,2,2,2,2,2,2,2,2,2,2,2,4),(0.,0.752880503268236,1.50600787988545,3.0154687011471,
3.75167336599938,4.48789219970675,5.22323407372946,5.95855322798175,6.59868084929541,
7.23885375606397,8.52010929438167,9.82978009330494,11.1368800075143),.UNSPECIFIED.);
#459=EDGE_CURVE('E189',#95,#429,#458,.T.);
#460=ORIENTED_EDGE('',*,*,#459,.F.);
#461=EDGE_LOOP('',(#427,#431,#460));
#462=FACE_BOUND('',#461,.T.);
#463=ADVANCED_FACE('F412',(#462),#147,.T.);
#464=CARTESIAN_POINT('',(-10.9697705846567,2.00142755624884,-0.000199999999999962));
#465=CARTESIAN_POINT('',(-10.8492020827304,2.07102656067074,0.2086307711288));
#466=CARTESIAN_POINT('',(-10.7281840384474,2.13746669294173,0.418240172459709));
#467=CARTESIAN_POINT('',(-10.4851774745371,2.26315271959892,0.839139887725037));
#468=CARTESIAN_POINT('',(-10.3631886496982,2.32239624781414,1.05043073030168));
#469=CARTESIAN_POINT('',(-9.99525656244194,2.48818542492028,1.68770779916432));
#470=CARTESIAN_POINT('',(-9.74786083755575,2.58248555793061,2.11620976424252));
#471=CARTESIAN_POINT('',(-9.37764446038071,2.69306129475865,2.75744333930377));
#472=CARTESIAN_POINT('',(-9.2559298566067,2.72456017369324,2.96825921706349));
#473=CARTESIAN_POINT('',(-9.01193711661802,2.77738179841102,3.39086703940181));
#474=CARTESIAN_POINT('',(-8.88965896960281,2.79870434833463,3.60265900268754));
#475=CARTESIAN_POINT('',(-8.64489870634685,2.83062697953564,4.02659621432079));
#476=CARTESIAN_POINT('',(-8.52241700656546,2.84123980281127,4.23874074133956));
#477=CARTESIAN_POINT('',(-8.2773404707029,2.85151746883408,4.66322575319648));
#478=CARTESIAN_POINT('',(-8.15474563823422,2.85118264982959,4.87556623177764));
#479=CARTESIAN_POINT('',(-7.92555157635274,2.84032663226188,5.27254199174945));
#480=CARTESIAN_POINT('',(-7.81893617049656,2.83112973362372,5.45720529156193));
#481=CARTESIAN_POINT('',(-7.6059547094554,2.80463460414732,5.82610000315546));
#482=CARTESIAN_POINT('',(-7.49958867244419,2.78733580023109,6.01033138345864));
#483=CARTESIAN_POINT('',(-7.18090270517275,2.72369551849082,6.562311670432));
#484=CARTESIAN_POINT('',(-6.96914687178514,2.66561809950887,6.92908353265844));
#485=CARTESIAN_POINT('',(-6.5433889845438,2.52042398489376,7.66651782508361));
#486=CARTESIAN_POINT('',(-6.32944126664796,2.43269183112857,8.03708614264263));
#487=CARTESIAN_POINT('',(-5.90473630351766,2.23357626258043,8.77269671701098));
#488=CARTESIAN_POINT('',(-5.69397361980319,2.12223961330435,9.137748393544));
#489=CARTESIAN_POINT('',(-5.48471208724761,2.00142755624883,9.5002));
#490=B_SPLINE_CURVE_WITH_KNOTS('',3,(#464,#465,#466,#467,#468,#469,#470,#471,#472,#473,#474,
#475,#476,#477,#478,#479,#480,#481,#482,#483,#484,#485,#486,#487,#488,#489),.UNSPECIFIED.,.F.,
.F.,(4,2,2,2,2,2,2,2,2,2,2,2,4),(0.,0.752880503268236,1.50600787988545,3.0154687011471,
3.75167336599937,4.48789219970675,5.22323407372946,5.95855322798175,6.59868084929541,
7.23885375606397,8.52010929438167,9.82978009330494,11.1368800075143),.UNSPECIFIED.);
#491=CARTESIAN_POINT('',(-5.48482755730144,2.00149422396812,9.5));
#492=VERTEX_POINT('',#491);
#493=EDGE_CURVE('E371',#41,#492,#490,.T.);
#494=ORIENTED_EDGE('',*,*,#493,.T.);
#495=EDGE_CURVE('E369',#492,#43,#416,.T.);
#496=ORIENTED_EDGE('',*,*,#495,.T.);
#497=ORIENTED_EDGE('',*,*,#44,.F.);
#498=EDGE_LOOP('',(#494,#496,#497));
#499=FACE_BOUND('',#498,.T.);
#500=ADVANCED_FACE('F429',(#499),#289,.T.);
#501=ORIENTED_EDGE('',*,*,#100,.T.);
#502=CARTESIAN_POINT('',(-10.9696551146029,-2.00149422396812,0.));
#503=VERTEX_POINT('',#502);
#504=EDGE_CURVE('E406',#503,#95,#458,.T.);
#505=ORIENTED_EDGE('',*,*,#504,.F.);
#506=CARTESIAN_POINT('',(-5.48471208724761,-2.00142755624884,-9.5002));
#507=CARTESIAN_POINT('',(-5.6052805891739,-2.07102656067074,-9.2913692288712));
#508=CARTESIAN_POINT('',(-5.72629863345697,-2.13746669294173,-9.08175982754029));
#509=CARTESIAN_POINT('',(-5.96930519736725,-2.26315271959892,-8.66086011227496));
#510=CARTESIAN_POINT('',(-6.09129402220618,-2.32239624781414,-8.44956926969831));
#511=CARTESIAN_POINT('',(-6.45922610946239,-2.48818542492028,-7.81229220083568));
#512=CARTESIAN_POINT('',(-6.70662183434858,-2.58248555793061,-7.38379023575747));
#513=CARTESIAN_POINT('',(-7.07683821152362,-2.69306129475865,-6.74255666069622));
#514=CARTESIAN_POINT('',(-7.19855281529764,-2.72456017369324,-6.53174078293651));
#515=CARTESIAN_POINT('',(-7.44254555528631,-2.77738179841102,-6.10913296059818));
#516=CARTESIAN_POINT('',(-7.56482370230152,-2.79870434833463,-5.89734099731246));
#517=CARTESIAN_POINT('',(-7.80958396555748,-2.83062697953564,-5.47340378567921));
#518=CARTESIAN_POINT('',(-7.93206566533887,-2.84123980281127,-5.26125925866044));
#519=CARTESIAN_POINT('',(-8.17714220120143,-2.85151746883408,-4.83677424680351));
#520=CARTESIAN_POINT('',(-8.29973703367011,-2.85118264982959,-4.62443376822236));
#521=CARTESIAN_POINT('',(-8.5289310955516,-2.84032663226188,-4.22745800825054));
#522=CARTESIAN_POINT('',(-8.63554650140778,-2.83112973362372,-4.04279470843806));
#523=CARTESIAN_POINT('',(-8.84852796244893,-2.80463460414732,-3.67389999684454));
#524=CARTESIAN_POINT('',(-8.95489399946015,-2.78733580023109,-3.48966861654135));
#525=CARTESIAN_POINT('',(-9.27357996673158,-2.72369551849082,-2.937688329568));
#526=CARTESIAN_POINT('',(-9.48533580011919,-2.66561809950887,-2.57091646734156));
#527=CARTESIAN_POINT('',(-9.91109368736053,-2.52042398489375,-1.83348217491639));
#528=CARTESIAN_POINT('',(-10.1250414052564,-2.43269183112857,-1.46291385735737));
#529=CARTESIAN_POINT('',(-10.5497463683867,-2.23357626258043,-0.727303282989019));
#530=CARTESIAN_POINT('',(-10.7605090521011,-2.12223961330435,-0.362251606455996));
#531=CARTESIAN_POINT('',(-10.9697705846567,-2.00142755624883,0.000200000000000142));
#532=B_SPLINE_CURVE_WITH_KNOTS('',3,(#506,#507,#508,#509,#510,#511,#512,#513,#514,#515,#516,
#517,#518,#519,#520,#521,#522,#523,#524,#525,#526,#527,#528,#529,#530,#531),.UNSPECIFIED.,.F.,
.F.,(4,2,2,2,2,2,2,2,2,2,2,2,4),(0.,0.752880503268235,1.50600787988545,3.0154687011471,
3.75167336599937,4.48789219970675,5.22323407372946,5.95855322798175,6.5986808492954,
7.23885375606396,8.52010929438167,9.82978009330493,11.1368800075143),.UNSPECIFIED.);
#533=EDGE_CURVE('E219',#99,#503,#532,.T.);
#534=ORIENTED_EDGE('',*,*,#533,.F.);
#535=EDGE_LOOP('',(#501,#505,#534));
#536=FACE_BOUND('',#535,.T.);
#537=ADVANCED_FACE('F427',(#536),#147,.T.);
#538=CARTESIAN_POINT('',(-5.48471208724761,2.00142755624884,-9.5002));
#539=CARTESIAN_POINT('',(-5.6052805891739,2.07102656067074,-9.2913692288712));
#540=CARTESIAN_POINT('',(-5.72629863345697,2.13746669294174,-9.08175982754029));
#541=CARTESIAN_POINT('',(-5.96930519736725,2.26315271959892,-8.66086011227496));
#542=CARTESIAN_POINT('',(-6.09129402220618,2.32239624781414,-8.44956926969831));
#543=CARTESIAN_POINT('',(-6.4592261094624,2.48818542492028,-7.81229220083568));
#544=CARTESIAN_POINT('',(-6.70662183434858,2.58248555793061,-7.38379023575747));
#545=CARTESIAN_POINT('',(-7.07683821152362,2.69306129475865,-6.74255666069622));
#546=CARTESIAN_POINT('',(-7.19855281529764,2.72456017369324,-6.53174078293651));
#547=CARTESIAN_POINT('',(-7.44254555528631,2.77738179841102,-6.10913296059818));
#548=CARTESIAN_POINT('',(-7.56482370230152,2.79870434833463,-5.89734099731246));
#549=CARTESIAN_POINT('',(-7.80958396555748,2.83062697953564,-5.47340378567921));
#550=CARTESIAN_POINT('',(-7.93206566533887,2.84123980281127,-5.26125925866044));
#551=CARTESIAN_POINT('',(-8.17714220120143,2.85151746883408,-4.83677424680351));
#552=CARTESIAN_POINT('',(-8.29973703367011,2.85118264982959,-4.62443376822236));
#553=CARTESIAN_POINT('',(-8.5289310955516,2.84032663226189,-4.22745800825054));
#554=CARTESIAN_POINT('',(-8.63554650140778,2.83112973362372,-4.04279470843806));
#555=CARTESIAN_POINT('',(-8.84852796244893,2.80463460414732,-3.67389999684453));
#556=CARTESIAN_POINT('',(-8.95489399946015,2.78733580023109,-3.48966861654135));
#557=CARTESIAN_POINT('',(-9.27357996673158,2.72369551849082,-2.93768832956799));
#558=CARTESIAN_POINT('',(-9.48533580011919,2.66561809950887,-2.57091646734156));
#559=CARTESIAN_POINT('',(-9.91109368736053,2.52042398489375,-1.83348217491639));
#560=CARTESIAN_POINT('',(-10.1250414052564,2.43269183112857,-1.46291385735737));
#561=CARTESIAN_POINT('',(-10.5497463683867,2.23357626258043,-0.72730328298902));
#562=CARTESIAN_POINT('',(-10.7605090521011,2.12223961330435,-0.362251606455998));
#563=CARTESIAN_POINT('',(-10.9697705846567,2.00142755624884,0.00020000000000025));
#564=B_SPLINE_CURVE_WITH_KNOTS('',3,(#538,#539,#540,#541,#542,#543,#544,#545,#546,#547,#548,
#549,#550,#551,#552,#553,#554,#555,#556,#557,#558,#559,#560,#561,#562,#563),.UNSPECIFIED.,.F.,
.F.,(4,2,2,2,2,2,2,2,2,2,2,2,4),(0.,0.752880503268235,1.50600787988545,3.0154687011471,
3.75167336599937,4.48789219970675,5.22323407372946,5.95855322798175,6.5986808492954,
7.23885375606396,8.52010929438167,9.82978009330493,11.1368800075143),.UNSPECIFIED.);
#565=CARTESIAN_POINT('',(-10.9696551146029,2.00149422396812,0.));
#566=VERTEX_POINT('',#565);
#567=EDGE_CURVE('E263',#59,#566,#564,.T.);
#568=ORIENTED_EDGE('',*,*,#567,.T.);
#569=EDGE_CURVE('E381',#566,#41,#490,.T.);
#570=ORIENTED_EDGE('',*,*,#569,.T.);
#571=ORIENTED_EDGE('',*,*,#62,.F.);
#572=EDGE_LOOP('',(#568,#570,#571));
#573=FACE_BOUND('',#572,.T.);
#574=ADVANCED_FACE('F421',(#573),#289,.T.);
#575=ORIENTED_EDGE('',*,*,#104,.T.);
#576=CARTESIAN_POINT('',(-5.48482755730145,-2.00149422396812,-9.49999999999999));
#577=VERTEX_POINT('',#576);
#578=EDGE_CURVE('E235',#577,#99,#532,.T.);
#579=ORIENTED_EDGE('',*,*,#578,.F.);
#580=CARTESIAN_POINT('',(16.8188633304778,2.81751395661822,-9.5));
#581=CARTESIAN_POINT('',(16.4183500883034,2.61620642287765,-9.5));
#582=CARTESIAN_POINT('',(16.0171570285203,2.41623761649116,-9.5));
#583=CARTESIAN_POINT('',(15.2130991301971,2.01962708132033,-9.5));
#584=CARTESIAN_POINT('',(14.8102341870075,1.82298556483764,-9.5));
#585=CARTESIAN_POINT('',(14.0017844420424,1.4333257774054,-9.5));
#586=CARTESIAN_POINT('',(13.5961958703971,1.24031531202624,-9.5));
#587=CARTESIAN_POINT('',(12.7827179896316,0.859216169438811,-9.5));
#588=CARTESIAN_POINT('',(12.3748287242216,0.67112739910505,-9.5));
#589=CARTESIAN_POINT('',(11.537358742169,0.292449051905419,-9.5));
#590=CARTESIAN_POINT('',(11.1076477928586,0.102146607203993,-9.5));
#591=CARTESIAN_POINT('',(10.2445855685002,-0.270106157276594,-9.5));
#592=CARTESIAN_POINT('',(9.81123413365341,-0.452056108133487,-9.5));
#593=CARTESIAN_POINT('',(8.94045769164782,-0.805201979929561,-9.5));
#594=CARTESIAN_POINT('',(8.50303531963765,-0.976404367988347,-9.5));
#595=CARTESIAN_POINT('',(7.62309223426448,-1.30515393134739,-9.5));
#596=CARTESIAN_POINT('',(7.18057207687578,-1.46270258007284,-9.5));
#597=CARTESIAN_POINT('',(6.46275750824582,-1.70238160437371,-9.5));
#598=CARTESIAN_POINT('',(6.18930979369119,-1.79002659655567,-9.5));
#599=CARTESIAN_POINT('',(5.64007283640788,-1.9576279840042,-9.5));
#600=CARTESIAN_POINT('',(5.36428350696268,-2.03758409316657,-9.5));
#601=CARTESIAN_POINT('',(4.53319488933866,-2.26409391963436,-9.5));
#602=CARTESIAN_POINT('',(3.9740783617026,-2.39732227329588,-9.5));
#603=CARTESIAN_POINT('',(3.13352758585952,-2.56129439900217,-9.5));
#604=CARTESIAN_POINT('',(2.85548786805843,-2.60969970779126,-9.5));
#605=CARTESIAN_POINT('',(2.2974962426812,-2.69402319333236,-9.5));
#606=CARTESIAN_POINT('',(2.01754436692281,-2.72994157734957,-9.5));
#607=CARTESIAN_POINT('',(1.45632964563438,-2.78821437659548,-9.5));
#608=CARTESIAN_POINT('',(1.17506733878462,-2.81057394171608,-9.5));
#609=CARTESIAN_POINT('',(0.611764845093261,-2.84102373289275,-9.5));
#610=CARTESIAN_POINT('',(0.329724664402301,-2.84911407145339,-9.5));
#611=CARTESIAN_POINT('',(-0.236413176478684,-2.8507537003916,-9.5));
#612=CARTESIAN_POINT('',(-0.520511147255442,-2.84419874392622,-9.5));
#613=CARTESIAN_POINT('',(-1.08799392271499,-2.8165616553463,-9.5));
#614=CARTESIAN_POINT('',(-1.37137871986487,-2.79547937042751,-9.5));
#615=CARTESIAN_POINT('',(-1.93687689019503,-2.73947689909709,-9.5));
#616=CARTESIAN_POINT('',(-2.21898973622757,-2.7045514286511,-9.5));
#617=CARTESIAN_POINT('',(-2.78131252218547,-2.62192625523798,-9.5));
#618=CARTESIAN_POINT('',(-3.06152243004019,-2.57422633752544,-9.49999999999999));
#619=CARTESIAN_POINT('',(-3.90869402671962,-2.4119698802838,-9.49999999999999));
#620=CARTESIAN_POINT('',(-4.47224297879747,-2.27931766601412,-9.49999999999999));
#621=CARTESIAN_POINT('',(-5.30985754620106,-2.05301216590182,-9.49999999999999));
#622=CARTESIAN_POINT('',(-5.58780518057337,-1.97301304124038,-9.49999999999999));
#623=CARTESIAN_POINT('',(-6.14131764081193,-1.80514200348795,-9.49999999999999));
#624=CARTESIAN_POINT('',(-6.4168825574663,-1.71727039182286,-9.49999999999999));
#625=CARTESIAN_POINT('',(-7.13891911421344,-1.47722823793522,-9.49999999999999));
#626=CARTESIAN_POINT('',(-7.58352700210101,-1.31946861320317,-9.49999999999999));
#627=CARTESIAN_POINT('',(-8.4675783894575,-0.990079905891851,-9.49999999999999));
#628=CARTESIAN_POINT('',(-8.90702131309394,-0.818449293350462,-9.49999999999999));
#629=CARTESIAN_POINT('',(-9.78178536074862,-0.464290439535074,-9.49999999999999));
#630=CARTESIAN_POINT('',(-10.2171037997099,-0.281755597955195,-9.49999999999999));
#631=CARTESIAN_POINT('',(-11.0840547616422,0.0917784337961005,-9.49999999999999));
#632=CARTESIAN_POINT('',(-11.5156874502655,0.282777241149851,-9.49999999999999));
#633=CARTESIAN_POINT('',(-12.3567622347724,0.662842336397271,-9.49999999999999));
#634=CARTESIAN_POINT('',(-12.7663368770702,0.851616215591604,-9.49999999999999));
#635=CARTESIAN_POINT('',(-13.5831621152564,1.23413764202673,-9.49999999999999));
#636=CARTESIAN_POINT('',(-13.9904126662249,1.42788528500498,-9.49999999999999));
#637=CARTESIAN_POINT('',(-14.8021509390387,1.8190499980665,-9.49999999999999));
#638=CARTESIAN_POINT('',(-15.2066425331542,2.01645904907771,-9.49999999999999));
#639=CARTESIAN_POINT('',(-16.0139388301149,2.41463385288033,-9.49999999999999));
#640=CARTESIAN_POINT('',(-16.4167436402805,2.61539938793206,-9.49999999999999));
#641=CARTESIAN_POINT('',(-16.8188633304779,2.81751395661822,-9.49999999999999));
#642=B_SPLINE_CURVE_WITH_KNOTS('',3,(#580,#581,#582,#583,#584,#585,#586,#587,#588,#589,#590,
#591,#592,#593,#594,#595,#596,#597,#598,#599,#600,#601,#602,#603,#604,#605,#606,#607,#608,#609,
#610,#611,#612,#613,#614,#615,#616,#617,#618,#619,#620,#621,#622,#623,#624,#625,#626,#627,#628,
#629,#630,#631,#632,#633,#634,#635,#636,#637,#638,#639,#640,#641),.UNSPECIFIED.,.F.,.F.,(4,2,2,
2,2,2,2,2,2,2,2,2,2,2,2,2,2,2,2,2,2,2,2,2,2,2,2,2,2,2,4),(0.,1.34478189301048,2.68964927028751,
4.03713684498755,5.38459890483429,6.79442275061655,8.20430880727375,9.61333819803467,
11.0222153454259,11.883557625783,12.7449319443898,14.4673746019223,15.3138133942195,
16.1602381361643,17.0063411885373,17.8524375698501,18.7045757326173,19.5567228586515,
20.4091955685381,21.2616826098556,22.9965895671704,23.864217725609,24.7318126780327,
26.1467947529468,27.5619331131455,28.977936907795,30.3938767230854,31.7467902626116,
33.0997298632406,34.4499924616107,35.8001678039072),.UNSPECIFIED.);
#643=EDGE_CURVE('E226',#103,#577,#642,.T.);
#644=ORIENTED_EDGE('',*,*,#643,.F.);
#645=EDGE_LOOP('',(#575,#579,#644));
#646=FACE_BOUND('',#645,.T.);
#647=ADVANCED_FACE('F420',(#646),#147,.T.);
#648=CARTESIAN_POINT('',(16.8188633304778,-2.81751395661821,-9.5));
#649=CARTESIAN_POINT('',(16.4183500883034,-2.61620642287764,-9.5));
#650=CARTESIAN_POINT('',(16.0171570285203,-2.41623761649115,-9.5));
#651=CARTESIAN_POINT('',(15.2130991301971,-2.01962708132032,-9.5));
#652=CARTESIAN_POINT('',(14.8102341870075,-1.82298556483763,-9.5));
#653=CARTESIAN_POINT('',(14.0017844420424,-1.4333257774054,-9.5));
#654=CARTESIAN_POINT('',(13.5961958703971,-1.24031531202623,-9.5));
#655=CARTESIAN_POINT('',(12.7827179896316,-0.859216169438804,-9.5));
#656=CARTESIAN_POINT('',(12.3748287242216,-0.671127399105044,-9.5));
#657=CARTESIAN_POINT('',(11.537358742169,-0.292449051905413,-9.5));
#658=CARTESIAN_POINT('',(11.1076477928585,-0.102146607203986,-9.5));
#659=CARTESIAN_POINT('',(10.2445855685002,0.270106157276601,-9.5));
#660=CARTESIAN_POINT('',(9.8112341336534,0.452056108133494,-9.5));
#661=CARTESIAN_POINT('',(8.94045769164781,0.805201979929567,-9.5));
#662=CARTESIAN_POINT('',(8.50303531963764,0.976404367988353,-9.5));
#663=CARTESIAN_POINT('',(7.62309223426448,1.3051539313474,-9.5));
#664=CARTESIAN_POINT('',(7.18057207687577,1.46270258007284,-9.5));
#665=CARTESIAN_POINT('',(6.46275750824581,1.70238160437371,-9.5));
#666=CARTESIAN_POINT('',(6.18930979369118,1.79002659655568,-9.5));
#667=CARTESIAN_POINT('',(5.64007283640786,1.9576279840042,-9.5));
#668=CARTESIAN_POINT('',(5.36428350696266,2.03758409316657,-9.5));
#669=CARTESIAN_POINT('',(4.53319488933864,2.26409391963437,-9.5));
#670=CARTESIAN_POINT('',(3.97407836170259,2.39732227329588,-9.5));
#671=CARTESIAN_POINT('',(3.13352758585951,2.56129439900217,-9.5));
#672=CARTESIAN_POINT('',(2.85548786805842,2.60969970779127,-9.5));
#673=CARTESIAN_POINT('',(2.29749624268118,2.69402319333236,-9.5));
#674=CARTESIAN_POINT('',(2.0175443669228,2.72994157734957,-9.5));
#675=CARTESIAN_POINT('',(1.45632964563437,2.78821437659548,-9.5));
#676=CARTESIAN_POINT('',(1.17506733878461,2.81057394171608,-9.5));
#677=CARTESIAN_POINT('',(0.611764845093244,2.84102373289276,-9.5));
#678=CARTESIAN_POINT('',(0.329724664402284,2.84911407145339,-9.5));
#679=CARTESIAN_POINT('',(-0.236413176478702,2.8507537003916,-9.5));
#680=CARTESIAN_POINT('',(-0.52051114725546,2.84419874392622,-9.5));
#681=CARTESIAN_POINT('',(-1.08799392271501,2.8165616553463,-9.5));
#682=CARTESIAN_POINT('',(-1.37137871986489,2.79547937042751,-9.5));
#683=CARTESIAN_POINT('',(-1.93687689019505,2.73947689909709,-9.5));
#684=CARTESIAN_POINT('',(-2.21898973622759,2.70455142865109,-9.5));
#685=CARTESIAN_POINT('',(-2.78131252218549,2.62192625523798,-9.5));
#686=CARTESIAN_POINT('',(-3.06152243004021,2.57422633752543,-9.49999999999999));
#687=CARTESIAN_POINT('',(-3.90869402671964,2.4119698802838,-9.49999999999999));
#688=CARTESIAN_POINT('',(-4.47224297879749,2.27931766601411,-9.49999999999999));
#689=CARTESIAN_POINT('',(-5.30985754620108,2.05301216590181,-9.49999999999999));
#690=CARTESIAN_POINT('',(-5.58780518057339,1.97301304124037,-9.49999999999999));
#691=CARTESIAN_POINT('',(-6.14131764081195,1.80514200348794,-9.49999999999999));
#692=CARTESIAN_POINT('',(-6.41688255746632,1.71727039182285,-9.49999999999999));
#693=CARTESIAN_POINT('',(-7.13891911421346,1.47722823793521,-9.49999999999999));
#694=CARTESIAN_POINT('',(-7.58352700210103,1.31946861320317,-9.49999999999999));
#695=CARTESIAN_POINT('',(-8.46757838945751,0.990079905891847,-9.49999999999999));
#696=CARTESIAN_POINT('',(-8.90702131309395,0.818449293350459,-9.49999999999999));
#697=CARTESIAN_POINT('',(-9.78178536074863,0.464290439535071,-9.49999999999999));
#698=CARTESIAN_POINT('',(-10.2171037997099,0.281755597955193,-9.49999999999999));
#699=CARTESIAN_POINT('',(-11.0840547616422,-0.0917784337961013,-9.49999999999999));
#700=CARTESIAN_POINT('',(-11.5156874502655,-0.282777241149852,-9.49999999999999));
#701=CARTESIAN_POINT('',(-12.3567622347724,-0.66284233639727,-9.49999999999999));
#702=CARTESIAN_POINT('',(-12.7663368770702,-0.851616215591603,-9.49999999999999));
#703=CARTESIAN_POINT('',(-13.5831621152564,-1.23413764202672,-9.49999999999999));
#704=CARTESIAN_POINT('',(-13.9904126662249,-1.42788528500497,-9.49999999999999));
#705=CARTESIAN_POINT('',(-14.8021509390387,-1.81904999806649,-9.49999999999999));
#706=CARTESIAN_POINT('',(-15.2066425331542,-2.01645904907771,-9.49999999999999));
#707=CARTESIAN_POINT('',(-16.0139388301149,-2.41463385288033,-9.49999999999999));
#708=CARTESIAN_POINT('',(-16.4167436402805,-2.61539938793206,-9.49999999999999));
#709=CARTESIAN_POINT('',(-16.8188633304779,-2.81751395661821,-9.49999999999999));
#710=B_SPLINE_CURVE_WITH_KNOTS('',3,(#648,#649,#650,#651,#652,#653,#654,#655,#656,#657,#658,
#659,#660,#661,#662,#663,#664,#665,#666,#667,#668,#669,#670,#671,#672,#673,#674,#675,#676,#677,
#678,#679,#680,#681,#682,#683,#684,#685,#686,#687,#688,#689,#690,#691,#692,#693,#694,#695,#696,
#697,#698,#699,#700,#701,#702,#703,#704,#705,#706,#707,#708,#709),.UNSPECIFIED.,.F.,.F.,(4,2,2,
2,2,2,2,2,2,2,2,2,2,2,2,2,2,2,2,2,2,2,2,2,2,2,2,2,2,2,4),(0.,1.34478189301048,2.68964927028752,
4.03713684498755,5.38459890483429,6.79442275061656,8.20430880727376,9.61333819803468,
11.0222153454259,11.883557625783,12.7449319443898,14.4673746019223,15.3138133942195,
16.1602381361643,17.0063411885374,17.8524375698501,18.7045757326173,19.5567228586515,
20.4091955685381,21.2616826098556,22.9965895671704,23.864217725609,24.7318126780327,
26.1467947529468,27.5619331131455,28.977936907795,30.3938767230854,31.7467902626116,
33.0997298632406,34.4499924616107,35.8001678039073),.UNSPECIFIED.);
#711=CARTESIAN_POINT('',(-5.48482755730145,2.00149422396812,-9.49999999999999));
#712=VERTEX_POINT('',#711);
#713=EDGE_CURVE('E253',#55,#712,#710,.T.);
#714=ORIENTED_EDGE('',*,*,#713,.T.);
#715=EDGE_CURVE('E262',#712,#59,#564,.T.);
#716=ORIENTED_EDGE('',*,*,#715,.T.);
#717=ORIENTED_EDGE('',*,*,#60,.F.);
#718=EDGE_LOOP('',(#714,#716,#717));
#719=FACE_BOUND('',#718,.T.);
#720=ADVANCED_FACE('F418',(#719),#289,.T.);
#721=ORIENTED_EDGE('',*,*,#108,.T.);
#722=CARTESIAN_POINT('',(5.48482755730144,-2.00149422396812,-9.5));
#723=VERTEX_POINT('',#722);
#724=EDGE_CURVE('E234',#723,#103,#642,.T.);
#725=ORIENTED_EDGE('',*,*,#724,.F.);
#726=EDGE_CURVE('E236',#107,#723,#206,.T.);
#727=ORIENTED_EDGE('',*,*,#726,.F.);
#728=EDGE_LOOP('',(#721,#725,#727));
#729=FACE_BOUND('',#728,.T.);
#730=ADVANCED_FACE('F203',(#729),#147,.T.);
#731=CARTESIAN_POINT('',(5.48482755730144,2.00149422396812,-9.5));
#732=VERTEX_POINT('',#731);
#733=EDGE_CURVE('E269',#51,#732,#316,.T.);
#734=ORIENTED_EDGE('',*,*,#733,.T.);
#735=EDGE_CURVE('E261',#732,#55,#710,.T.);
#736=ORIENTED_EDGE('',*,*,#735,.T.);
#737=ORIENTED_EDGE('',*,*,#56,.F.);
#738=EDGE_LOOP('',(#734,#736,#737));
#739=FACE_BOUND('',#738,.T.);
#740=ADVANCED_FACE('F340',(#739),#289,.T.);
#741=CARTESIAN_POINT('',(5.48482755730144,2.85,9.5));
#742=DIRECTION('',(-0.866025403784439,0.,-0.5));
#743=DIRECTION('',(-0.5,0.,0.866025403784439));
#744=AXIS2_PLACEMENT_3D('',#741,#742,#743);
#745=PLANE('',#744);
#746=ORIENTED_EDGE('',*,*,#421,.F.);
#747=DIRECTION('',(0.,-1.,0.));
#748=VECTOR('',#747,1.);
#749=CARTESIAN_POINT('',(5.48482755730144,2.85,9.5));
#750=LINE('',#749,#748);
#751=EDGE_CURVE('E163',#418,#214,#750,.T.);
#752=ORIENTED_EDGE('',*,*,#751,.T.);
#753=ORIENTED_EDGE('',*,*,#215,.T.);
#754=ORIENTED_EDGE('',*,*,#177,.T.);
#755=DIRECTION('',(0.,-1.,0.));
#756=VECTOR('',#755,1.);
#757=CARTESIAN_POINT('',(10.9696551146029,2.85,0.));
#758=LINE('',#757,#756);
#759=EDGE_CURVE('E277',#318,#176,#758,.T.);
#760=ORIENTED_EDGE('',*,*,#759,.F.);
#761=ORIENTED_EDGE('',*,*,#349,.F.);
#762=EDGE_LOOP('',(#746,#752,#753,#754,#760,#761));
#763=FACE_BOUND('',#762,.T.);
#764=ADVANCED_FACE('F161',(#763),#745,.F.);
#765=CARTESIAN_POINT('',(-5.48482755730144,2.85,9.5));
#766=DIRECTION('',(0.,0.,-1.));
#767=DIRECTION('',(-1.,0.,0.));
#768=AXIS2_PLACEMENT_3D('',#765,#766,#767);
#769=PLANE('',#768);
#770=ORIENTED_EDGE('',*,*,#495,.F.);
#771=DIRECTION('',(0.,-1.,0.));
#772=VECTOR('',#771,1.);
#773=CARTESIAN_POINT('',(-5.48482755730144,2.85,9.5));
#774=LINE('',#773,#772);
#775=EDGE_CURVE('E282',#492,#429,#774,.T.);
#776=ORIENTED_EDGE('',*,*,#775,.T.);
#777=ORIENTED_EDGE('',*,*,#430,.T.);
#778=ORIENTED_EDGE('',*,*,#280,.T.);
#779=ORIENTED_EDGE('',*,*,#751,.F.);
#780=ORIENTED_EDGE('',*,*,#419,.F.);
#781=EDGE_LOOP('',(#770,#776,#777,#778,#779,#780));
#782=FACE_BOUND('',#781,.T.);
#783=ADVANCED_FACE('F196',(#782),#769,.F.);
#784=CARTESIAN_POINT('',(-10.9696551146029,2.85,0.));
#785=DIRECTION('',(0.866025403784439,0.,-0.5));
#786=DIRECTION('',(-0.5,0.,-0.866025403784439));
#787=AXIS2_PLACEMENT_3D('',#784,#785,#786);
#788=PLANE('',#787);
#789=ORIENTED_EDGE('',*,*,#569,.F.);
#790=DIRECTION('',(0.,-1.,0.));
#791=VECTOR('',#790,1.);
#792=CARTESIAN_POINT('',(-10.9696551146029,2.85,0.));
#793=LINE('',#792,#791);
#794=EDGE_CURVE('E286',#566,#503,#793,.T.);
#795=ORIENTED_EDGE('',*,*,#794,.T.);
#796=ORIENTED_EDGE('',*,*,#504,.T.);
#797=ORIENTED_EDGE('',*,*,#459,.T.);
#798=ORIENTED_EDGE('',*,*,#775,.F.);
#799=ORIENTED_EDGE('',*,*,#493,.F.);
#800=EDGE_LOOP('',(#789,#795,#796,#797,#798,#799));
#801=FACE_BOUND('',#800,.T.);
#802=ADVANCED_FACE('F382',(#801),#788,.F.);
#803=CARTESIAN_POINT('',(-5.48482755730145,2.85,-9.49999999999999));
#804=DIRECTION('',(0.866025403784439,0.,0.5));
#805=DIRECTION('',(0.5,0.,-0.866025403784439));
#806=AXIS2_PLACEMENT_3D('',#803,#804,#805);
#807=PLANE('',#806);
#808=ORIENTED_EDGE('',*,*,#715,.F.);
#809=DIRECTION('',(0.,-1.,0.));
#810=VECTOR('',#809,1.);
#811=CARTESIAN_POINT('',(-5.48482755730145,2.85,-9.49999999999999));
#812=LINE('',#811,#810);
#813=EDGE_CURVE('E290',#712,#577,#812,.T.);
#814=ORIENTED_EDGE('',*,*,#813,.T.);
#815=ORIENTED_EDGE('',*,*,#578,.T.);
#816=ORIENTED_EDGE('',*,*,#533,.T.);
#817=ORIENTED_EDGE('',*,*,#794,.F.);
#818=ORIENTED_EDGE('',*,*,#567,.F.);
#819=EDGE_LOOP('',(#808,#814,#815,#816,#817,#818));
#820=FACE_BOUND('',#819,.T.);
#821=ADVANCED_FACE('F247',(#820),#807,.F.);
#822=CARTESIAN_POINT('',(5.48482755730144,2.85,-9.5));
#823=DIRECTION('',(0.,0.,1.));
#824=DIRECTION('',(1.,0.,0.));
#825=AXIS2_PLACEMENT_3D('',#822,#823,#824);
#826=PLANE('',#825);
#827=ORIENTED_EDGE('',*,*,#735,.F.);
#828=DIRECTION('',(0.,-1.,0.));
#829=VECTOR('',#828,1.);
#830=CARTESIAN_POINT('',(5.48482755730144,2.85,-9.5));
#831=LINE('',#830,#829);
#832=EDGE_CURVE('E157',#732,#723,#831,.T.);
#833=ORIENTED_EDGE('',*,*,#832,.T.);
#834=ORIENTED_EDGE('',*,*,#724,.T.);
#835=ORIENTED_EDGE('',*,*,#643,.T.);
#836=ORIENTED_EDGE('',*,*,#813,.F.);
#837=ORIENTED_EDGE('',*,*,#713,.F.);
#838=EDGE_LOOP('',(#827,#833,#834,#835,#836,#837));
#839=FACE_BOUND('',#838,.T.);
#840=ADVANCED_FACE('F243',(#839),#826,.F.);
#841=CARTESIAN_POINT('',(10.9696551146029,2.85,0.));
#842=DIRECTION('',(-0.866025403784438,0.,0.5));
#843=DIRECTION('',(0.5,0.,0.866025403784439));
#844=AXIS2_PLACEMENT_3D('',#841,#842,#843);
#845=PLANE('',#844);
#846=ORIENTED_EDGE('',*,*,#319,.F.);
#847=ORIENTED_EDGE('',*,*,#759,.T.);
#848=ORIENTED_EDGE('',*,*,#207,.T.);
#849=ORIENTED_EDGE('',*,*,#726,.T.);
#850=ORIENTED_EDGE('',*,*,#832,.F.);
#851=ORIENTED_EDGE('',*,*,#733,.F.);
#852=EDGE_LOOP('',(#846,#847,#848,#849,#850,#851));
#853=FACE_BOUND('',#852,.T.);
#854=ADVANCED_FACE('F246',(#853),#845,.F.);
#855=CARTESIAN_POINT('',(0.,-2.85,0.));
#856=DIRECTION('',(0.,-1.,0.));
#857=DIRECTION('',(0.,0.,-1.));
#858=AXIS2_PLACEMENT_3D('',#855,#856,#857);
#859=CONICAL_SURFACE('',#858,6.50000000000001,0.785398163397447);
#860=ORIENTED_EDGE('',*,*,#127,.F.);
#861=EDGE_LOOP('',(#860));
#862=FACE_BOUND('',#861,.T.);
#863=ORIENTED_EDGE('',*,*,#79,.F.);
#864=EDGE_LOOP('',(#863));
#865=FACE_BOUND('',#864,.T.);
#866=ADVANCED_FACE('F498',(#862,#865),#859,.F.);
#867=CARTESIAN_POINT('',(0.,2.35,0.));
#868=DIRECTION('',(0.,1.,0.));
#869=DIRECTION('',(0.,0.,1.));
#870=AXIS2_PLACEMENT_3D('',#867,#868,#869);
#871=CONICAL_SURFACE('',#870,6.,0.785398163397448);
#872=ORIENTED_EDGE('',*,*,#31,.F.);
#873=EDGE_LOOP('',(#872));
#874=FACE_BOUND('',#873,.T.);
#875=ORIENTED_EDGE('',*,*,#138,.F.);
#876=EDGE_LOOP('',(#875));
#877=FACE_BOUND('',#876,.T.);
#878=ADVANCED_FACE('F41',(#874,#877),#871,.F.);
#879=CLOSED_SHELL('',(#66,#114,#142,#211,#284,#353,#426,#463,#500,#537,#574,#647,#720,#730,#740,
#764,#783,#802,#821,#840,#854,#866,#878));
#880=MANIFOLD_SOLID_BREP('B2',#879);
#881=ADVANCED_BREP_SHAPE_REPRESENTATION('',(#18,#880),#14);
#882=SHAPE_DEFINITION_REPRESENTATION(#9,#881);
ENDSEC;
END-ISO-10303-21;
